One B-rep face of a CAD part: STEP entity #1110.
In plain terms, the planar face has unit normal (1, 0, 0).
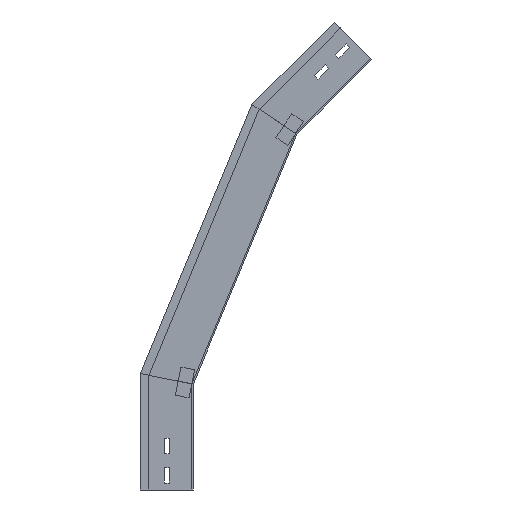
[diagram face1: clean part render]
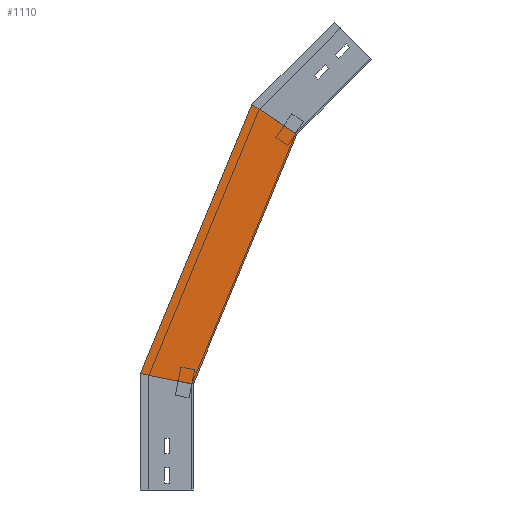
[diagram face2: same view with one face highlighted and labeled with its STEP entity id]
Its self-contained STEP definition (entity closure, numbers rounded to 3 decimals):
#33 = CARTESIAN_POINT ( 'NONE',  ( 0., 6.318, 134.746 ) ) ;
#35 = ORIENTED_EDGE ( 'NONE', *, *, #1261, .T. ) ;
#51 = DIRECTION ( 'NONE',  ( 0., 0., -1. ) ) ;
#153 = CARTESIAN_POINT ( 'NONE',  ( 0., 75.609, 163.448 ) ) ;
#160 = VERTEX_POINT ( 'NONE', #398 ) ;
#201 = CARTESIAN_POINT ( 'NONE',  ( 0., -146.568, 503.846 ) ) ;
#257 = EDGE_CURVE ( 'NONE', #656, #160, #1312, .T. ) ;
#303 = VERTEX_POINT ( 'NONE', #201 ) ;
#327 = DIRECTION ( 'NONE',  ( 0., -0.831, -0.556 ) ) ;
#380 = CARTESIAN_POINT ( 'NONE',  ( 0., 75., 164.918 ) ) ;
#396 = ORIENTED_EDGE ( 'NONE', *, *, #1297, .F. ) ;
#398 = CARTESIAN_POINT ( 'NONE',  ( 0., -82.986, 546.33 ) ) ;
#422 = LINE ( 'NONE', #535, #1471 ) ;
#436 = DIRECTION ( 'NONE',  ( 0., -0.981, -0.195 ) ) ;
#535 = CARTESIAN_POINT ( 'NONE',  ( 0., 6.318, 134.746 ) ) ;
#544 = DIRECTION ( 'NONE',  ( 0., -0.383, 0.924 ) ) ;
#625 = FACE_OUTER_BOUND ( 'NONE', #1002, .T. ) ;
#656 = VERTEX_POINT ( 'NONE', #380 ) ;
#715 = EDGE_CURVE ( 'NONE', #656, #891, #874, .T. ) ;
#760 = VECTOR ( 'NONE', #436, 1000. ) ;
#804 = ORIENTED_EDGE ( 'NONE', *, *, #715, .F. ) ;
#817 = LINE ( 'NONE', #1368, #1241 ) ;
#874 = LINE ( 'NONE', #880, #760 ) ;
#880 = CARTESIAN_POINT ( 'NONE',  ( 0., -28.701, 144.291 ) ) ;
#884 = ORIENTED_EDGE ( 'NONE', *, *, #257, .T. ) ;
#891 = VERTEX_POINT ( 'NONE', #1043 ) ;
#1002 = EDGE_LOOP ( 'NONE', ( #884, #35, #396, #804 ) ) ;
#1043 = CARTESIAN_POINT ( 'NONE',  ( 0., 0., 150. ) ) ;
#1077 = DIRECTION ( 'NONE',  ( 1., 0., 0. ) ) ;
#1110 = ADVANCED_FACE ( 'NONE', ( #625 ), #1419, .T. ) ;
#1241 = VECTOR ( 'NONE', #327, 1000. ) ;
#1261 = EDGE_CURVE ( 'NONE', #160, #303, #817, .T. ) ;
#1297 = EDGE_CURVE ( 'NONE', #891, #303, #422, .T. ) ;
#1312 = LINE ( 'NONE', #153, #1357 ) ;
#1334 = DIRECTION ( 'NONE',  ( 0., -0.383, 0.924 ) ) ;
#1357 = VECTOR ( 'NONE', #1334, 1000. ) ;
#1368 = CARTESIAN_POINT ( 'NONE',  ( 0., -211.373, 460.544 ) ) ;
#1407 = AXIS2_PLACEMENT_3D ( 'NONE', #33, #1077, #51 ) ;
#1419 = PLANE ( 'NONE',  #1407 ) ;
#1471 = VECTOR ( 'NONE', #544, 1000. ) ;
